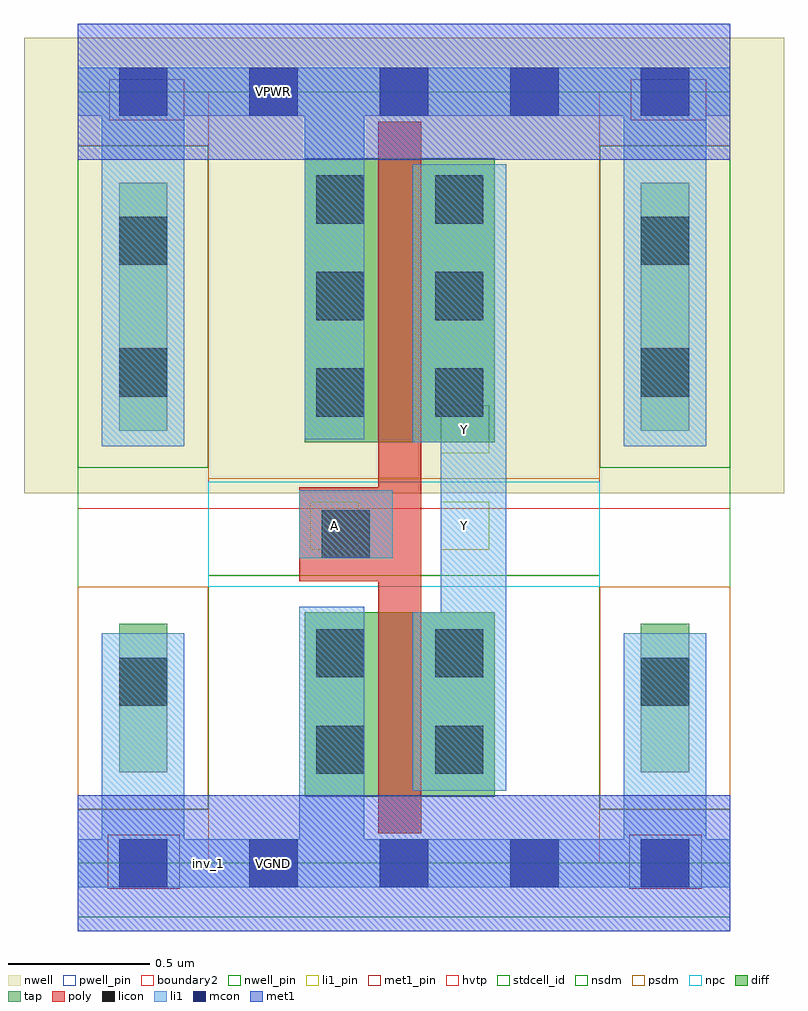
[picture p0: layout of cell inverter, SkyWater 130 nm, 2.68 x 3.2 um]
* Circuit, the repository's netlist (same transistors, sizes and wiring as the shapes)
.subckt inverter A VGND VPWR Y
XMN1 Y A VGND VGND sky130_fd_pr__nfet_01v8 w=0.65 l=0.15 nf=1 m=1
XMP1 Y A VPWR VPWR sky130_fd_pr__pfet_01v8_hvt w=1 l=0.15 nf=1 m=1
.ends inverter

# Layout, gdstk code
import gdstk
lib = gdstk.Library(unit=1e-6, precision=1e-09)
def R(c, l, rs):  # rectangles x0, y0, x1, y1
    for r in rs: c.add(gdstk.rectangle(r[:2], r[2:], *l))
def A(c, l, x, y, w, h, nx, ny, dx, dy):  # array of equal rectangles
    R(c, l, [(x+i*dx, y+j*dy, x+i*dx+w, y+j*dy+h) for i in range(nx) for j in range(ny)])
def P(c, l, *ps):  # polygons
    for p in ps: c.add(gdstk.Polygon(p, *l))
nwell_pin = (64, 16)
nwell = (64, 20)
diff = (65, 20)
tap = (65, 44)
poly = (66, 20)
licon = (66, 44)
li1_pin = (67, 16)
li1 = (67, 20)
mcon = (67, 44)
met1_pin = (68, 16)
met1 = (68, 20)
hvtp = (78, 44)
stdcell_id = (81, 4)
nsdm = (93, 44)
psdm = (94, 20)
npc = (95, 20)
pwell_pin = (122, 16)
boundary2 = (236, 0)

sky130_fd_sc_hd__tapvpwr = lib.new_cell('sky130_fd_sc_hd__tapvpwrvgnd_1')
R(sky130_fd_sc_hd__tapvpwr, nwell, [(-0.19,1.305,0.65,2.91)])
R(sky130_fd_sc_hd__tapvpwr, tap, [(0.145,0.32,0.315,0.845), (0.145,1.525,0.315,2.4)])
R(sky130_fd_sc_hd__tapvpwr, licon, [(0.145,0.555,0.315,0.725), (0.145,1.645,0.315,1.815), (0.145,2.11,0.315,2.28)])
R(sky130_fd_sc_hd__tapvpwr, li1, [(0,-0.085,0.46,0.085), (0.085,0,0.375,0.81), (0.085,1.47,0.375,2.72), (0,2.635,0.46,2.805)])
R(sky130_fd_sc_hd__tapvpwr, mcon, [(0.145,-0.085,0.315,0.085), (0.145,2.635,0.315,2.805)])
R(sky130_fd_sc_hd__tapvpwr, met1_pin, [(0.105,-0.09,0.36,0.1), (0.11,2.62,0.375,2.765)])
R(sky130_fd_sc_hd__tapvpwr, met1, [(0,-0.24,0.46,0.24), (0,2.48,0.46,2.96)])
R(sky130_fd_sc_hd__tapvpwr, hvtp, [(0,1.25,0.46,2.72)])
R(sky130_fd_sc_hd__tapvpwr, stdcell_id, [(0,0,0.46,2.72)])
R(sky130_fd_sc_hd__tapvpwr, nsdm, [(0,-0.19,0.46,0.19), (0,1.395,0.46,2.53)])
R(sky130_fd_sc_hd__tapvpwr, psdm, [(0,0.19,0.46,0.975), (0,2.53,0.46,2.91)])
sky130_fd_sc_hd__tapvpwr.add(gdstk.Label('VPWR', (0.23,2.72), layer=68, texttype=5))
sky130_fd_sc_hd__tapvpwr.add(gdstk.Label('VGND', (0.23,0), layer=68, texttype=5))
sky130_fd_sc_hd__tapvpwr.add(gdstk.Label('tapvpwrvgnd_1', (0,0), layer=83, texttype=44))

inverter = lib.new_cell('inverter')
R(inverter, nwell_pin, [(0.145,2.635,0.315,2.805), (0.145,2.635,0.315,2.805)])
R(inverter, nwell, [(-0.19,1.305,1.57,2.91)])
R(inverter, diff, [(0.34,0.235,1.01,0.885), (0.34,1.485,1.01,2.485)])
P(inverter, poly, [(0.6,0.105),(0.6,0.995),(0.32,0.995),(0.32,1.325),(0.6,1.325),(0.6,2.615),(0.75,2.615),(0.75,0.105)])
A(inverter, licon, 0.38, 1.575, 0.17, 0.17, 1, 3, 0, 0.34)
A(inverter, licon, 0.8, 1.575, 0.17, 0.17, 1, 3, 0, 0.34)
R(inverter, licon, [(0.38,0.315,0.55,0.485), (0.8,0.315,0.97,0.485), (0.38,0.655,0.55,0.825), (0.8,0.655,0.97,0.825), (0.4,1.075,0.57,1.245)])
R(inverter, li1_pin, [(0.36,1.105,0.53,1.275), (0.82,1.105,0.99,1.275), (0.82,1.445,0.99,1.615)])
R(inverter, li1, [(0,-0.085,1.38,0.085), (0.32,0.005,0.55,0.905), (0.32,1.075,0.65,1.315), (0.34,1.495,0.55,2.675), (0,2.635,1.38,2.805)])
P(inverter, li1, [(0.72,0.255),(0.72,0.885),(0.82,0.885),(0.82,1.485),(0.72,1.485),(0.72,2.465),(1.05,2.465),(1.05,0.255)])
A(inverter, mcon, 0.145, -0.085, 0.17, 0.17, 3, 2, 0.46, 2.72)
R(inverter, met1_pin, [(0.145,-0.085,0.315,0.085), (0.145,-0.085,0.315,0.085), (0.145,2.635,0.315,2.805), (0.145,2.635,0.315,2.805)])
R(inverter, hvtp, [(0,1.25,1.38,2.72)])
R(inverter, stdcell_id, [(0,0,1.38,2.72)])
R(inverter, nsdm, [(0,-0.19,1.38,1.015)])
R(inverter, psdm, [(0,1.355,1.38,2.91)])
R(inverter, npc, [(0,0.975,1.38,1.345)])
R(inverter, pwell_pin, [(0.145,-0.085,0.315,0.085), (0.145,-0.085,0.315,0.085)])
R(inverter, boundary2, [(0,0,1.38,2.72)])
inverter.add(gdstk.FlexPath([(0,2.72),(1.38,2.72)], 0.48, ends="flush", simple_path=True, layer=68, datatype=20))  # met1
inverter.add(gdstk.FlexPath([(0,0),(1.38,0)], 0.48, ends="flush", simple_path=True, layer=68, datatype=20))  # met1
inverter.add(gdstk.Reference(sky130_fd_sc_hd__tapvpwr, (-0.46,0)))
inverter.add(gdstk.Reference(sky130_fd_sc_hd__tapvpwr, (1.38,0)))
inverter.add(gdstk.Label('VGND', (0.23,0), layer=68, texttype=5))
inverter.add(gdstk.Label('VPWR', (0.23,2.72), layer=68, texttype=5))
inverter.add(gdstk.Label('inv_1', (0,0), layer=83, texttype=44))
inverter.add(gdstk.Label('Y', (0.905,1.53), layer=67, texttype=5))
inverter.add(gdstk.Label('Y', (0.905,1.19), layer=67, texttype=5))
inverter.add(gdstk.Label('A', (0.445,1.19), layer=67, texttype=5))

lib.write_gds('inverter.gds')
